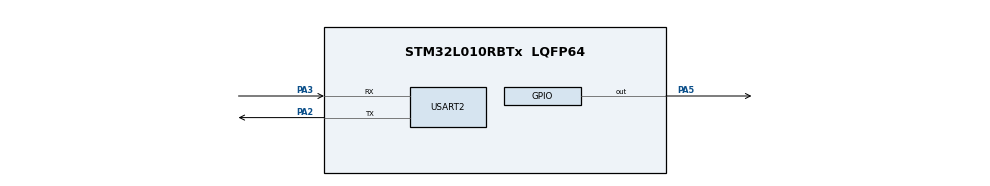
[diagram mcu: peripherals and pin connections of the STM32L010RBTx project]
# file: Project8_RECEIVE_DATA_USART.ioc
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Mcu.Family=STM32L0
Mcu.Name=STM32L010RBTx
Mcu.Package=LQFP64
PA2.Mode=Asynchronous
PA2.Signal=USART2_TX
PA3.Mode=Asynchronous
PA3.Signal=USART2_RX
PA5.Signal=GPIO_Output
PH0-OSC_IN.Mode=HSE-External-Oscillator
PH0-OSC_IN.Signal=RCC_OSC_IN
PH1-OSC_OUT.Mode=HSE-External-Oscillator
PH1-OSC_OUT.Signal=RCC_OSC_OUT
ProjectManager.HeapSize=0x200
ProjectManager.StackSize=0x400
ProjectManager.TargetToolchain=EWARM V8.32
RCC.AHBFreq_Value=2097000
RCC.APB1Freq_Value=2097000
RCC.APB1TimFreq_Value=2097000
RCC.APB2Freq_Value=2097000
RCC.APB2TimFreq_Value=2097000
RCC.HSE_VALUE=8000000
RCC.HSI16_VALUE=16000000
RCC.HSI48_VALUE=48000000
RCC.HSI_VALUE=16000000
RCC.LSEState=RCC_LSE_ON
RCC.LSE_VALUE=32768
RCC.MSI_VALUE=2097000
RCC.SYSCLKFreq_VALUE=2097000
RCC.VCOOutputFreq_Value=48000000
USART2.VirtualMode-Asynchronous=VM_ASYNC
board=NUCLEO-L010RB

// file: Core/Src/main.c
/* USER CODE BEGIN Header */
/**
  ******************************************************************************
  * @file           : main.c
  * @brief          : Main program body
  ******************************************************************************
  * @attention
  *
  * <h2><center>&copy; Copyright (c) 2021 STMicroelectronics.
  * All rights reserved.</center></h2>
  *
  * This software component is licensed by ST under BSD 3-Clause license,
  * the "License"; You may not use this file except in compliance with the
  * License. You may obtain a copy of the License at:
  *                        opensource.org/licenses/BSD-3-Clause
  *
  ******************************************************************************
  */
/* USER CODE END Header */
#include "main.h"

/* USER CODE BEGIN Includes */
#include <stdio.h>
#include <string.h>
/* USER CODE END Includes */

UART_HandleTypeDef huart2;

/* USER CODE BEGIN PV */
uint16_t contor=0;
uint16_t contor2=0;
char msg[100];

char* bufftr="Hello!\n\r";
uint8_t buffrec[5];

/* USER CODE END PV */

void SystemClock_Config(void);
static void MX_GPIO_Init(void);
static void MX_USART2_UART_Init(void);

int main(void)
{

  /* MCU Configuration--------------------------------------------------------*/

  /* Reset of all peripherals, Initializes the Flash interface and the Systick. */
  HAL_Init();

  /* Configure the system clock */
  SystemClock_Config();

  /* Initialize all configured peripherals */
  MX_GPIO_Init();
  MX_USART2_UART_Init();
  /* USER CODE BEGIN 2 */
  __HAL_UART_ENABLE_IT(&huart2, UART_IT_RXNE);
  __HAL_UART_ENABLE_IT(&huart2, UART_IT_TC);
  /* USER CODE END 2 */

  /* Infinite loop */
  while (1)
  {

    /* USER CODE BEGIN 3 */
  //  sprintf(msg, "Textul trimis de SENDER este: %hu\r\n", contor);
  // HAL_UART_Transmit(&huart2, msg, strlen(msg), 10);
 //  HAL_UART_Receive_IT(&huart2, msgPrimit, 13);
   HAL_UART_Receive_IT(&huart2, buffrec, 5);
   HAL_UART_Transmit_IT(&huart2, (uint8_t *)bufftr, 8);
   HAL_Delay(200);
  }
  /* USER CODE END 3 */
}

void SystemClock_Config(void)
{
  RCC_OscInitTypeDef RCC_OscInitStruct = {0};
  RCC_ClkInitTypeDef RCC_ClkInitStruct = {0};
  RCC_PeriphCLKInitTypeDef PeriphClkInit = {0};

  /** Configure the main internal regulator output voltage
  */
  __HAL_PWR_VOLTAGESCALING_CONFIG(PWR_REGULATOR_VOLTAGE_SCALE1);
  /** Initializes the RCC Oscillators according to the specified parameters
  * in the RCC_OscInitTypeDef structure.
  */
  RCC_OscInitStruct.OscillatorType = RCC_OSCILLATORTYPE_HSE;
  RCC_OscInitStruct.HSEState = RCC_HSE_ON;
  RCC_OscInitStruct.PLL.PLLState = RCC_PLL_ON;
  RCC_OscInitStruct.PLL.PLLSource = RCC_PLLSOURCE_HSE;
  RCC_OscInitStruct.PLL.PLLMUL = RCC_PLLMUL_8;
  RCC_OscInitStruct.PLL.PLLDIV = RCC_PLLDIV_2;
  if (HAL_RCC_OscConfig(&RCC_OscInitStruct) != HAL_OK)
  {
    Error_Handler();
  }
  /** Initializes the CPU, AHB and APB buses clocks
  */
  RCC_ClkInitStruct.ClockType = RCC_CLOCKTYPE_HCLK|RCC_CLOCKTYPE_SYSCLK
                              |RCC_CLOCKTYPE_PCLK1|RCC_CLOCKTYPE_PCLK2;
  RCC_ClkInitStruct.SYSCLKSource = RCC_SYSCLKSOURCE_PLLCLK;
  RCC_ClkInitStruct.AHBCLKDivider = RCC_SYSCLK_DIV1;
  RCC_ClkInitStruct.APB1CLKDivider = RCC_HCLK_DIV1;
  RCC_ClkInitStruct.APB2CLKDivider = RCC_HCLK_DIV1;

  if (HAL_RCC_ClockConfig(&RCC_ClkInitStruct, FLASH_LATENCY_1) != HAL_OK)
  {
    Error_Handler();
  }
  PeriphClkInit.PeriphClockSelection = RCC_PERIPHCLK_USART2;
  PeriphClkInit.Usart2ClockSelection = RCC_USART2CLKSOURCE_PCLK1;
  if (HAL_RCCEx_PeriphCLKConfig(&PeriphClkInit) != HAL_OK)
  {
    Error_Handler();
  }
}

static void MX_USART2_UART_Init(void)
{

  huart2.Instance = USART2;
  huart2.Init.BaudRate = 9600;
  huart2.Init.WordLength = UART_WORDLENGTH_8B;
  huart2.Init.StopBits = UART_STOPBITS_1;
  huart2.Init.Parity = UART_PARITY_NONE;
  huart2.Init.Mode = UART_MODE_TX_RX;
  huart2.Init.HwFlowCtl = UART_HWCONTROL_NONE;
  huart2.Init.OverSampling = UART_OVERSAMPLING_16;
  huart2.Init.OneBitSampling = UART_ONE_BIT_SAMPLE_DISABLE;
  huart2.AdvancedInit.AdvFeatureInit = UART_ADVFEATURE_NO_INIT;
  if (HAL_UART_Init(&huart2) != HAL_OK)
  {
    Error_Handler();
  }

}

static void MX_GPIO_Init(void)
{
  GPIO_InitTypeDef GPIO_InitStruct = {0};

  /* GPIO Ports Clock Enable */
  __HAL_RCC_GPIOC_CLK_ENABLE();
  __HAL_RCC_GPIOH_CLK_ENABLE();
  __HAL_RCC_GPIOA_CLK_ENABLE();

  /*Configure GPIO pin : PC13 */
  GPIO_InitStruct.Pin = GPIO_PIN_13;
  GPIO_InitStruct.Mode = GPIO_MODE_IT_RISING;
  GPIO_InitStruct.Pull = GPIO_NOPULL;
  HAL_GPIO_Init(GPIOC, &GPIO_InitStruct);

  /* EXTI interrupt init*/
  HAL_NVIC_SetPriority(EXTI4_15_IRQn, 0, 0);
  HAL_NVIC_EnableIRQ(EXTI4_15_IRQn);

}

void Error_Handler(void)
{
  __disable_irq();
  while (1)
  {
  }
}

/************************ (C) COPYRIGHT STMicroelectronics *****END OF FILE****/
